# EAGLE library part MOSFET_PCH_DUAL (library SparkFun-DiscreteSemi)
Dual P-Channel -20VDS MOSFET Link to datasheet SparkFun Products: SparkFun FreeSoC2 Development Board

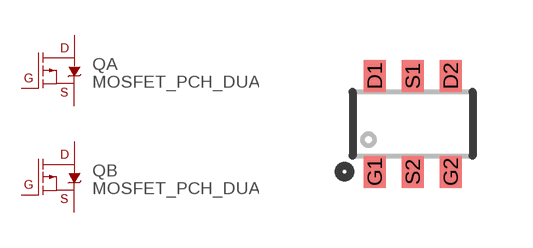
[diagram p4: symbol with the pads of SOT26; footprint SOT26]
Designator prefix Q; gates A=LABELED-PMOS B=LABELED-PMOS

## MOSFET_PCH_DUAL-DMP2240UDM (PROD_ID: TRANS-12444; VALUE: 2A/20V/150mΩ)  [SOT26]
D1  A:D
D2  B:D
G1  A:G
G2  B:G
S1  A:S
S2  B:S

## Footprint SOT26 (pad centres in mm)
Footprint for SOT-26 part DMP2240UDM
smd 0.55 x 0.8: D1 -0.95,1.2; D2 0.95,1.2; G1 -0.95,-1.2; G2 0.95,-1.2; S1 0,1.2; S2 0,-1.2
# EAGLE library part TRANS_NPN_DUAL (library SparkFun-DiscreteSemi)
Dual NPN Transistors in Single Package The MBT3904W1 puts two general purpose 3904 NPN transistors in a single package. Datasheet SparkFun Products: SparkFun ESP32 Thing

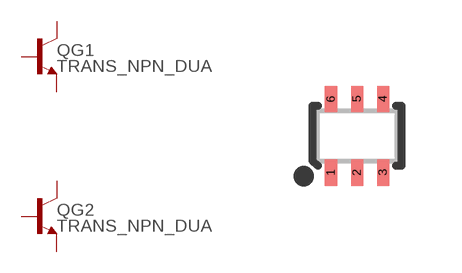
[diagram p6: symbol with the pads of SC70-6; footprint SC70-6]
Designator prefix Q; gates G1=NPN G2=NPN

## TRANS_NPN_DUAL-MBT3904DW1T1 (PROD_ID: TRANS-13337)  [SC70-6]
1  G2:E  pas
2  G2:B  pas
3  G1:C  pas
4  G1:E  pas
5  G1:B  pas
6  G2:C  pas

## Footprint SC70-6 (pad centres in mm)
SC-88/SC70-6/SOT-363 6-pin Package Example Datasheet
smd 0.3 x 0.66: 1 -0.65,-0.92; 2 0,-0.92; 3 0.65,-0.92; 4 0.65,0.92; 5 0,0.92; 6 -0.65,0.92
